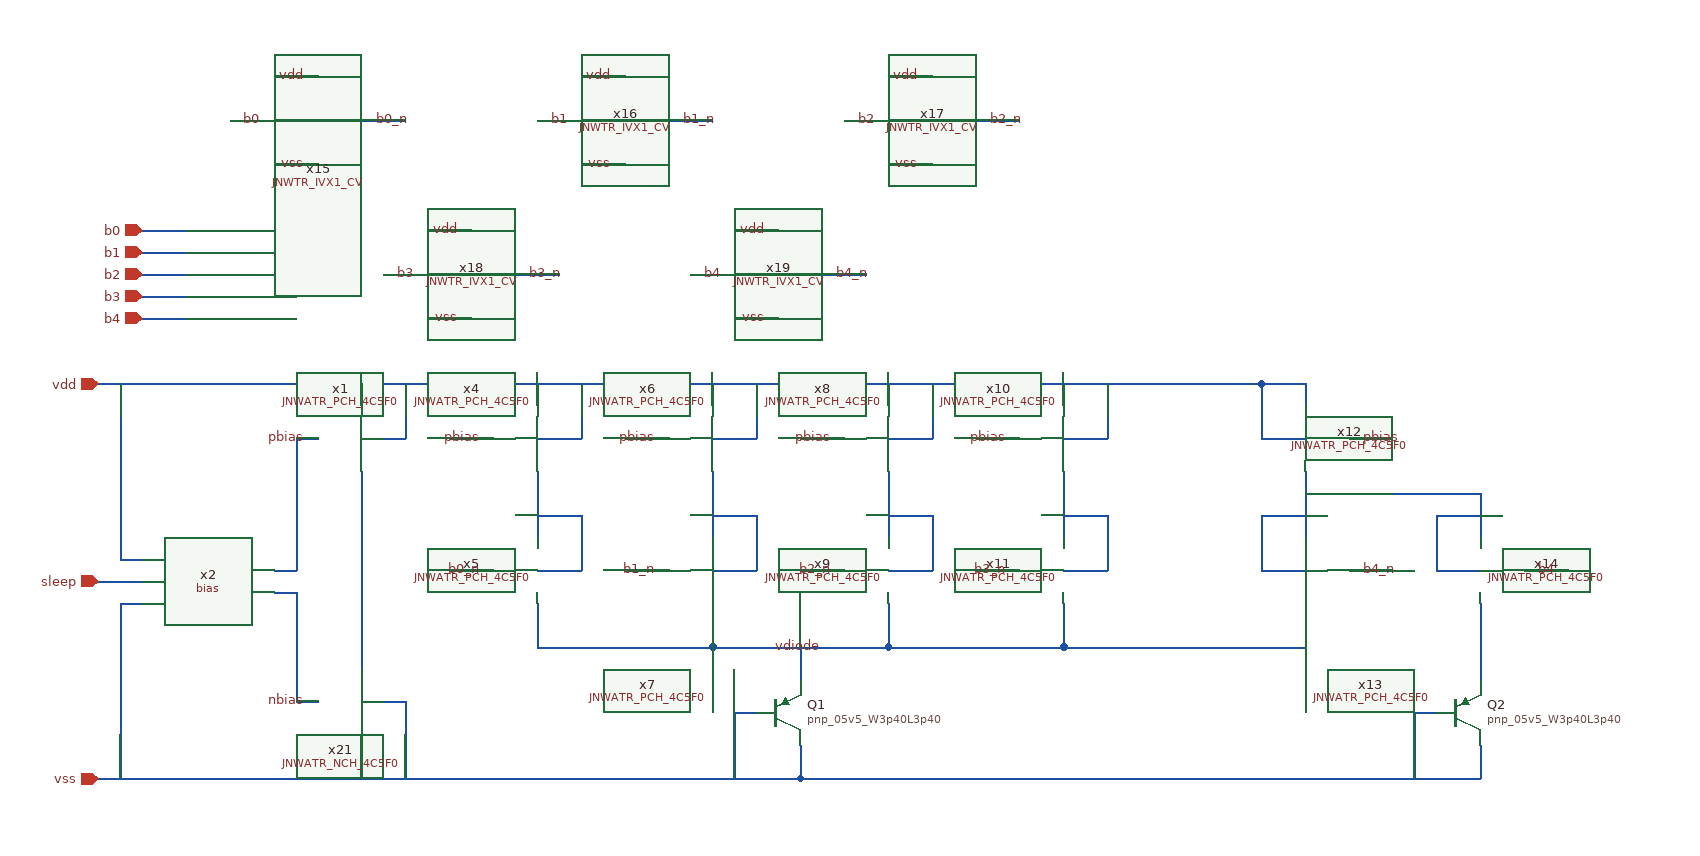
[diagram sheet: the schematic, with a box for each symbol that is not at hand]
v {xschem version=3.4.6 file_version=1.2}
G {}
K {}
V {}
S {}
E {}
N 680 -600 680 -580 {lab=vdd}
N 1080 -360 1080 -330 {lab=vdiode}
N 760 -550 800 -550 {lab=pbias}
N 840 -600 840 -580 {lab=vdd}
N 840 -520 840 -460 {lab=#net2}
N 840 -400 840 -360 {lab=vdiode}
N 760 -430 800 -430 {lab=b0_n}
N 840 -550 880 -550 {lab=vdd}
N 880 -600 880 -550 {lab=vdd}
N 840 -430 880 -430 {lab=#net2}
N 880 -480 880 -430 {lab=#net2}
N 840 -480 880 -480 {lab=#net2}
N 840 -360 1000 -360 {lab=vdiode}
N 920 -550 960 -550 {lab=pbias}
N 1000 -600 1000 -580 {lab=vdd}
N 1000 -520 1000 -460 {lab=#net3}
N 1000 -400 1000 -360 {lab=vdiode}
N 920 -430 960 -430 {lab=b1_n}
N 1000 -550 1040 -550 {lab=vdd}
N 1040 -600 1040 -550 {lab=vdd}
N 1000 -430 1040 -430 {lab=#net3}
N 1040 -480 1040 -430 {lab=#net3}
N 1000 -480 1040 -480 {lab=#net3}
N 1000 -360 1160 -360 {lab=vdiode}
N 1080 -550 1120 -550 {lab=pbias}
N 1160 -600 1160 -580 {lab=vdd}
N 1160 -520 1160 -460 {lab=#net4}
N 1160 -400 1160 -360 {lab=vdiode}
N 1080 -430 1120 -430 {lab=b2_n}
N 1160 -550 1200 -550 {lab=vdd}
N 1200 -600 1200 -550 {lab=vdd}
N 1160 -430 1200 -430 {lab=#net4}
N 1200 -480 1200 -430 {lab=#net4}
N 1160 -480 1200 -480 {lab=#net4}
N 1160 -360 1320 -360 {lab=vdiode}
N 1240 -550 1280 -550 {lab=pbias}
N 1320 -600 1320 -580 {lab=vdd}
N 1320 -520 1320 -460 {lab=#net5}
N 1320 -400 1320 -360 {lab=vdiode}
N 1240 -430 1280 -430 {lab=b3_n}
N 1320 -550 1360 -550 {lab=vdd}
N 1360 -600 1360 -550 {lab=vdd}
N 1320 -430 1360 -430 {lab=#net5}
N 1360 -480 1360 -430 {lab=#net5}
N 1320 -480 1360 -480 {lab=#net5}
N 440 -600 1500 -600 {lab=vdd}
N 1580 -550 1620 -550 {lab=pbias}
N 1540 -600 1540 -580 {lab=vdd}
N 1540 -520 1540 -460 {lab=#net6}
N 1540 -400 1540 -360 {lab=vdiode}
N 1580 -430 1620 -430 {lab=b4_n}
N 1500 -550 1540 -550 {lab=vdd}
N 1500 -600 1500 -550 {lab=vdd}
N 1500 -430 1540 -430 {lab=#net6}
N 1500 -480 1500 -430 {lab=#net6}
N 1500 -480 1540 -480 {lab=#net6}
N 1540 -500 1700 -500 {lab=#net6}
N 1700 -500 1700 -460 {lab=#net6}
N 1700 -400 1700 -330 {lab=#net7}
N 1740 -430 1780 -430 {lab=b4}
N 1660 -430 1700 -430 {lab=#net6}
N 1660 -480 1660 -430 {lab=#net6}
N 1660 -480 1700 -480 {lab=#net6}
N 1320 -360 1540 -360 {lab=vdiode}
N 1080 -270 1080 -240 {lab=vss}
N 1080 -240 1700 -240 {lab=vss}
N 1700 -270 1700 -240 {lab=vss}
N 1640 -300 1660 -300 {lab=vss}
N 1640 -300 1640 -240 {lab=vss}
N 1020 -300 1040 -300 {lab=vss}
N 1020 -300 1020 -240 {lab=vss}
N 440 -240 1080 -240 {lab=vss}
N 560 -840 600 -840 {lab=b0}
N 480 -720 520 -720 {lab=b1}
N 480 -700 520 -700 {lab=b2}
N 480 -680 520 -680 {lab=b3}
N 480 -660 520 -660 {lab=b4}
N 600 -880 640 -880 {lab=vdd}
N 600 -800 640 -800 {lab=vss}
N 680 -840 720 -840 {lab=b0_n}
N 840 -840 880 -840 {lab=b1}
N 880 -880 920 -880 {lab=vdd}
N 880 -800 920 -800 {lab=vss}
N 960 -840 1000 -840 {lab=b1_n}
N 1120 -840 1160 -840 {lab=b2}
N 1160 -880 1200 -880 {lab=vdd}
N 1160 -800 1200 -800 {lab=vss}
N 1240 -840 1280 -840 {lab=b2_n}
N 700 -700 740 -700 {lab=b3}
N 740 -740 780 -740 {lab=vdd}
N 740 -660 780 -660 {lab=vss}
N 820 -700 860 -700 {lab=b3_n}
N 980 -700 1020 -700 {lab=b4}
N 1020 -740 1060 -740 {lab=vdd}
N 1020 -660 1060 -660 {lab=vss}
N 1100 -700 1140 -700 {lab=b4_n}
N 480 -740 520 -740 {lab=b0}
N 680 -550 720 -550 {lab=vdd}
N 720 -600 720 -550 {lab=vdd}
N 680 -520 680 -340 {lab=#net1}
N 680 -310 720 -310 {lab=vss}
N 720 -310 720 -240 {lab=vss}
N 680 -280 680 -240 {lab=vss}
N 440 -420 480 -420 {lab=sleep}
N 460 -600 460 -440 {lab=vdd}
N 460 -400 460 -240 {lab=vss}
N 620 -410 620 -310 {lab=nbias}
N 620 -310 640 -310 {lab=nbias}
N 620 -550 620 -430 {lab=pbias}
N 620 -550 640 -550 {lab=pbias}
N 600 -410 620 -410 {lab=nbias}
N 600 -430 620 -430 {lab=pbias}
N 460 -400 480 -400 {lab=vss}
N 460 -440 480 -440 {lab=vdd}
N 1500 -600 1540 -600 {lab=vdd}
C {JNW_ATR_SKY130A/JNWATR_PCH_4C5F0.sym} 640 -550 0 0 {name=x1 }
C {JNW_ATR_SKY130A/JNWATR_PCH_4C5F0.sym} 800 -550 0 0 {name=x4 }
C {JNW_ATR_SKY130A/JNWATR_PCH_4C5F0.sym} 800 -430 0 0 {name=x5 }
C {JNW_ATR_SKY130A/JNWATR_PCH_4C5F0.sym} 960 -550 0 0 {name=x6 }
C {JNW_ATR_SKY130A/JNWATR_PCH_4C5F0.sym} 960 -430 0 0 {name=x7 }
C {JNW_ATR_SKY130A/JNWATR_PCH_4C5F0.sym} 1120 -550 0 0 {name=x8 }
C {JNW_ATR_SKY130A/JNWATR_PCH_4C5F0.sym} 1120 -430 0 0 {name=x9 }
C {JNW_ATR_SKY130A/JNWATR_PCH_4C5F0.sym} 1280 -550 0 0 {name=x10 }
C {JNW_ATR_SKY130A/JNWATR_PCH_4C5F0.sym} 1280 -430 0 0 {name=x11 }
C {JNW_ATR_SKY130A/JNWATR_PCH_4C5F0.sym} 1580 -550 0 1 {name=x12 }
C {JNW_ATR_SKY130A/JNWATR_PCH_4C5F0.sym} 1580 -430 0 1 {name=x13 }
C {devices/lab_wire.sym} 1590 -430 0 1 {name=p2 sig_type=std_logic lab=b4_n
}
C {devices/lab_wire.sym} 1270 -430 0 0 {name=p3 sig_type=std_logic lab=b3_n
}
C {devices/lab_wire.sym} 1110 -430 0 0 {name=p4 sig_type=std_logic lab=b2_n
}
C {devices/lab_wire.sym} 950 -430 0 0 {name=p5 sig_type=std_logic lab=b1_n
}
C {devices/lab_wire.sym} 790 -430 0 0 {name=p6 sig_type=std_logic lab=b0_n
}
C {JNW_ATR_SKY130A/JNWATR_PCH_4C5F0.sym} 1740 -430 0 1 {name=x14 }
C {devices/ipin.sym} 440 -600 0 0 {name=p14 lab=vdd}
C {sky130_fd_pr/pnp_05v5.sym} 1060 -300 0 0 {name=Q1
model=pnp_05v5_W3p40L3p40
m=1
spiceprefix=X
}
C {sky130_fd_pr/pnp_05v5.sym} 1680 -300 0 0 {name=Q2
model=pnp_05v5_W3p40L3p40
m=1
spiceprefix=X
}
C {devices/ipin.sym} 440 -240 0 0 {name=p15 lab=vss}
C {devices/ipin.sym} 480 -720 0 0 {name=p17 lab=b1}
C {devices/ipin.sym} 480 -700 0 0 {name=p18 lab=b2}
C {devices/ipin.sym} 480 -680 0 0 {name=p19 lab=b3}
C {devices/ipin.sym} 480 -660 0 0 {name=p20 lab=b4}
C {JNW_TR_SKY130A/JNWTR_IVX1_CV.sym} 600 -840 0 0 {name=x15 }
C {devices/lab_wire.sym} 630 -800 2 1 {name=p23 sig_type=std_logic lab=vss}
C {devices/lab_wire.sym} 630 -880 0 0 {name=p24 sig_type=std_logic lab=vdd}
C {JNW_TR_SKY130A/JNWTR_IVX1_CV.sym} 880 -840 0 0 {name=x16 }
C {devices/lab_wire.sym} 910 -800 2 1 {name=p26 sig_type=std_logic lab=vss}
C {devices/lab_wire.sym} 910 -880 0 0 {name=p27 sig_type=std_logic lab=vdd}
C {JNW_TR_SKY130A/JNWTR_IVX1_CV.sym} 1160 -840 0 0 {name=x17 }
C {devices/lab_wire.sym} 1190 -800 2 1 {name=p30 sig_type=std_logic lab=vss}
C {devices/lab_wire.sym} 1190 -880 0 0 {name=p31 sig_type=std_logic lab=vdd}
C {JNW_TR_SKY130A/JNWTR_IVX1_CV.sym} 740 -700 0 0 {name=x18 }
C {devices/lab_wire.sym} 770 -660 2 1 {name=p34 sig_type=std_logic lab=vss}
C {devices/lab_wire.sym} 770 -740 0 0 {name=p35 sig_type=std_logic lab=vdd}
C {JNW_TR_SKY130A/JNWTR_IVX1_CV.sym} 1020 -700 0 0 {name=x19 }
C {devices/lab_wire.sym} 1050 -660 2 1 {name=p38 sig_type=std_logic lab=vss}
C {devices/lab_wire.sym} 1050 -740 0 0 {name=p39 sig_type=std_logic lab=vdd}
C {devices/lab_wire.sym} 590 -840 0 0 {name=p16 sig_type=std_logic lab=b0}
C {devices/lab_wire.sym} 730 -700 0 0 {name=p25 sig_type=std_logic lab=b3}
C {devices/lab_wire.sym} 870 -840 0 0 {name=p28 sig_type=std_logic lab=b1}
C {devices/lab_wire.sym} 1010 -700 0 0 {name=p29 sig_type=std_logic lab=b4}
C {devices/lab_wire.sym} 1150 -840 0 0 {name=p32 sig_type=std_logic lab=b2}
C {devices/ipin.sym} 480 -740 0 0 {name=p7 lab=b0}
C {devices/lab_wire.sym} 830 -700 0 1 {name=p36 sig_type=std_logic lab=b3_n}
C {devices/lab_wire.sym} 690 -840 0 1 {name=p37 sig_type=std_logic lab=b0_n}
C {devices/lab_wire.sym} 970 -840 0 1 {name=p40 sig_type=std_logic lab=b1_n}
C {devices/lab_wire.sym} 1110 -700 0 1 {name=p41 sig_type=std_logic lab=b4_n}
C {devices/lab_wire.sym} 1250 -840 0 1 {name=p45 sig_type=std_logic lab=b2_n}
C {devices/lab_wire.sym} 1750 -430 0 1 {name=p1 sig_type=std_logic lab=b4
}
C {devices/lab_wire.sym} 950 -550 0 0 {name=p9 sig_type=std_logic lab=pbias
}
C {devices/lab_wire.sym} 1110 -550 0 0 {name=p8 sig_type=std_logic lab=pbias
}
C {devices/lab_wire.sym} 1270 -550 0 0 {name=p10 sig_type=std_logic lab=pbias
}
C {devices/lab_wire.sym} 1590 -550 0 1 {name=p11 sig_type=std_logic lab=pbias
}
C {JNW_ATR_SKY130A/JNWATR_NCH_4C5F0.sym} 640 -310 0 0 {name=x21 }
C {devices/lab_wire.sym} 790 -550 0 0 {name=p12 sig_type=std_logic lab=pbias
}
C {LELO_TORD_SKY130A/bias.sym} 540 -420 0 0 {name=x2}
C {devices/ipin.sym} 440 -420 0 0 {name=p33 lab=sleep}
C {devices/lab_wire.sym} 630 -550 0 0 {name=p13 sig_type=std_logic lab=pbias
}
C {devices/lab_wire.sym} 630 -310 2 1 {name=p21 sig_type=std_logic lab=nbias
}
C {devices/lab_wire.sym} 1100 -360 0 0 {name=p22 sig_type=std_logic lab=vdiode
}
